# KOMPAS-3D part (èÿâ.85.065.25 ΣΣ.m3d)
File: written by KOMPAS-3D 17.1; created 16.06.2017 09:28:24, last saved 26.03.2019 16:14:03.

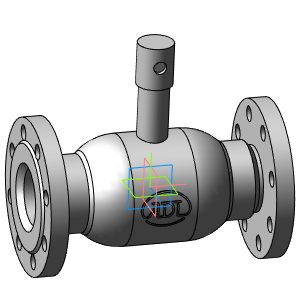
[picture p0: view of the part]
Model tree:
1. Операция без истории:2  (labels: Сталь 20  ГОСТ 1050-88)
